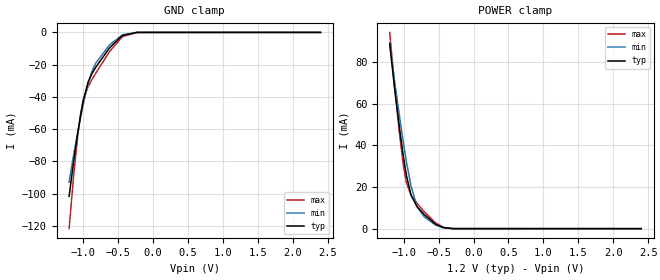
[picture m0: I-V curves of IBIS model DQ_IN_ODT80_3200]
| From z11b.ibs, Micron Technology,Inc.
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| MODEL DQ_IN_ODT80_3200 (Data Input with 80ohm ODT, 1600-3200Mbps)
[Model]   DQ_IN_ODT80_3200
Model_type   Input
Vinl = 905.000mV
Vinh = 1015.000mV
|   typ   min   max
|C_comp   0.764pF   0.710pF   0.826pF
C_comp_power_clamp   0.382pF   0.355pF   0.413pF
C_comp_gnd_clamp   0.382pF   0.355pF   0.413pF
| Note: C_comp changes when the ODT circuit is enabled.
|[Model Spec]
| Dynamic Overshoot Parameters from DDR4 Specification
|D_overshoot_ampl_h   0.40   NA   NA
|D_overshoot_ampl_l   0.40   NA   NA
|D_overshoot_area_h   0.0800n   NA   NA
|D_overshoot_area_l   0.0800n   NA   NA
[Voltage Range]   1.2000V   1.1400V   1.2600V
| Junction Temperature (Ambient temp is 35C typ, 95C min, 0C max)
[Temperature Range]   50.0   110.0   0.0
[Add Submodel]
| Submodel Name   Mode
80ohm_ODT_3200   Non-Driving
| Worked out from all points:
|   GND clamp passes 1 mA (typ) near -0.39 V on its own axis
|   POWER clamp passes 1 mA (typ) near -0.48 V on its own axis
[GND_clamp]
|   Voltage   I(typ)   I(min)   I(max)
-1.2V     -101.7mA   -92.86mA   -121.7mA
-1.135V   -79.96mA   -75.85mA   -88.92mA
-1.08V    -63.49mA   -62.76mA   -65.41mA
-1.036V   -51.56mA   -52.84mA   -50.64mA
-992.7mV  -41.38mA   -43.58mA   -41.02mA
-927.3mV  -30.76mA   -31.6mA    -33.57mA
-872.7mV  -25.55mA   -24.13mA   -29.29mA
-818.2mV  -21.61mA   -19.01mA   -25.29mA
-621.8mV  -9.659mA   -7.799mA   -11.96mA
-436.4mV  -1.919mA   -1.478mA   -2.611mA
-229.1mV  -17.22uA   -19.75uA   -20.83uA
2.4V      0A         0A         0A
[Power Clamp]
|   Voltage   I(typ)   I(min)   I(max)
-1.2V     88.83mA    89.6mA     94.34mA
-1.135V   68.72mA    72.21mA    70.04mA
-1.058V   47.72mA    53.58mA    44.98mA
-1.004V   34.46mA    41.14mA    30.25mA
-960mV    25.46mA    31.98mA    21.99mA
-894.5mV  16.03mA    20.41mA    16.05mA
-807.3mV  10.5mA     10.53mA    12.15mA
-709.1mV  6.909mA    5.768mA    8.277mA
-545.5mV  2.223mA    1.735mA    2.842mA
-436.4mV  532.9uA    427.3uA    716.1uA
-294.5mV  16.21uA    18.63uA    20.69uA
2.4V      0A         0A         0A
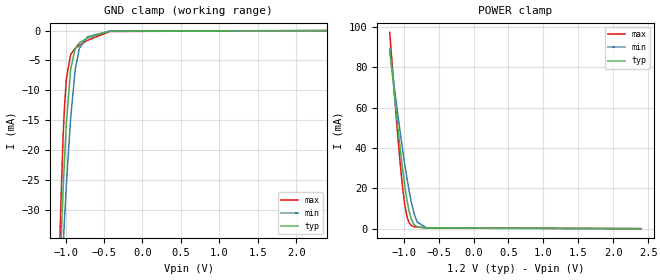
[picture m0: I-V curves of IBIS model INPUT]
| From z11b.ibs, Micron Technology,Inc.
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| MODEL INPUT (Add/Cmd/Ctrl Input Model, 1600-3200Mbps)
[Model]   INPUT
Model_type   Input
Vinl = 510.000mV
Vinh = 690.000mV
|   typ   min   max
|C_comp   0.306pF   0.256pF   0.356pF
C_comp_power_clamp   0.153pF   0.128pF   0.178pF
C_comp_gnd_clamp   0.153pF   0.128pF   0.178pF
[Model Spec]
| Input threshold voltage corners
Vinl   0.5100V   0.4800V   0.5400V
Vinh   0.6900V   0.6600V   0.7200V
| Dynamic Overshoot Parameters from DDR4 Specification
|D_overshoot_ampl_h   0.30   NA   NA
|D_overshoot_ampl_l   0.30   NA   NA
|D_overshoot_area_h   0.1754n   NA   NA
|D_overshoot_area_l   0.1762n   NA   NA
[Receiver Thresholds]
Vth   =  0.600V
Vth_min  =  0.5880V
Vth_max  =  0.6120V
Vinh_ac  =  0.090V
Vinh_dc  =  0.065V
Vinl_ac  = -0.090V
Vinl_dc  = -0.065V
Tslew_ac =  5.000ns |Not specified, so set to high value
Threshold_sensitivity = 0.50
Reference_supply Power_clamp_ref
[Voltage Range]   1.2000V   1.1400V   1.2600V
[POWER Clamp Reference]   1.2000V   1.1400V   1.2600V
| Junction Temperature (Ambient temp is 35C typ, 95C min, 0C max)
[Temperature Range]   50.0   110.0   0.0
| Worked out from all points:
|   GND clamp passes 1 mA (typ) near -0.67 V on its own axis
|   POWER clamp passes 1 mA (typ) near -0.81 V on its own axis
[GND Clamp]
|   Voltage   I(typ)   I(min)   I(max)
-1.2V     -89.68mA   -83.76mA   -112.5mA
-1.08V    -42.27mA   -48.6mA    -37.43mA
-1.065V   -37.02mA   -44.48mA   -30.24mA
-1.035V   -27.36mA   -36.67mA   -18.41mA
-1.015V   -21.61mA   -31.62mA   -12.71mA
-990mV    -15.4mA    -25.73mA   -8.028mA
-935mV    -6.48mA    -14.64mA   -4.005mA
-875mV    -2.985mA   -6.456mA   -2.943mA
-820mV    -2.025mA   -2.921mA   -2.441mA
-715mV    -1.243mA   -1.044mA   -1.636mA
-425mV    -95.71uA   -64.44uA   -150uA
2.4V      0A         0A         0A
[POWER Clamp]
|   Voltage   I(typ)   I(min)   I(max)
-1.2V     89.29mA    88mA       97.25mA
-1.095V   53.78mA    59.42mA    50.04mA
-1.05V    39.66mA    47.81mA    32.16mA
-1.015V   29.47mA    39.09mA    20.17mA
-985mV    21.54mA    31.96mA    11.96mA
-955mV    14.57mA    25.34mA    6.252mA
-925mV    9.043mA    19.2mA     3.084mA
-890mV    4.569mA    12.96mA    1.546mA
-850mV    1.945mA    7.193mA    981.4uA
-805mV    853.4uA    3.217mA    763.2uA
-665mV    277.9uA    269.6uA    403.6uA
2.4V      0A         0A         0A
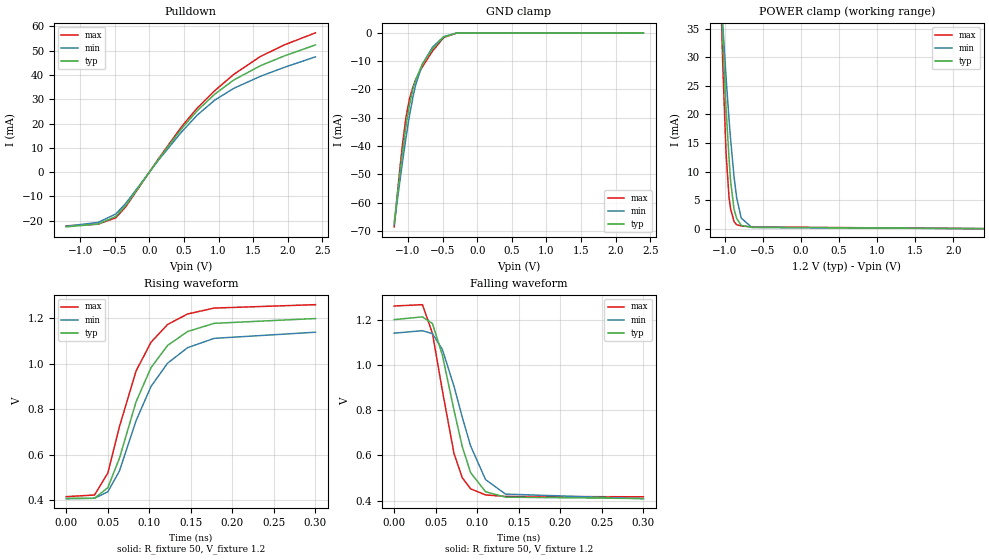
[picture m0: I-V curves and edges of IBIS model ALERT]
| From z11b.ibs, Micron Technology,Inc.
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| MODEL ALERT (ALERT_n Output Model, 1600-3200Mbps)
[Model]   ALERT
Model_type   Open_sink
Vmeas = 960.000mV
Vref = 1200.000mV
Cref = 0.0pF
Rref = 50.000Ohm
|   typ   min   max
|C_comp   0.806pF   0.756pF   0.856pF
C_comp_pulldown   0.806pF   0.756pF   0.856pF
[Model Spec]
| Timing spec test load voltage corners
Vref   1.2000V   1.1400V   1.2600V
[Voltage Range]   1.2000V   1.1400V   1.2600V
| Junction Temperature (Ambient temp is 35C typ, 95C min, 0C max)
[Temperature Range]   50.0   110.0   0.0
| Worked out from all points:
|   slope of the pulldown table from 0 to 0.18 V, typ, clamps not added: 25.2 ohm
|   GND clamp passes 1 mA (typ) near -0.46 V on its own axis
|   POWER clamp passes 1 mA (typ) near -0.82 V on its own axis
|   falling waveform, R_fixture 50, V_fixture 1.2: 20-80 % time 29.5ps typ, 35.7ps min, 25ps max; typ from 1.2 V to 0.409 V
|   rising waveform, R_fixture 50, V_fixture 1.2: 20-80 % time 50ps typ, 53ps min, 46.3ps max; typ from 0.409 V to 1.2 V
[Pulldown]
|   Voltage   I(typ)   I(min)   I(max)
-1.2V     -22.53mA   -22.3mA    -22.12mA
-740mV    -21.37mA   -20.69mA   -21.42mA
-485mV    -18.25mA   -17.25mA   -18.81mA
-340mV    -13.7mA    -12.84mA   -14.26mA
130mV     5.188mA    4.823mA    5.434mA
465mV     17.81mA    16.51mA    18.66mA
690mV     25.22mA    23.41mA    26.3mA
945mV     32.09mA    29.63mA    33.52mA
1.22V     37.91mA    34.47mA    40.23mA
1.605V    43.79mA    39.44mA    47.59mA
1.955V    47.87mA    43.16mA    52.41mA
2.4V      52.35mA    47.43mA    57.32mA
[GND Clamp]
|   Voltage   I(typ)   I(min)   I(max)
-1.2V     -67.18mA   -67.87mA   -68.61mA
-1.125V   -51.16mA   -53.75mA   -49.62mA
-1.08V    -42.22mA   -45.67mA   -39.36mA
-1.03V    -33.13mA   -37.16mA   -29.91mA
-980mV    -25.55mA   -29.4mA    -23.39mA
-925mV    -19.39mA   -22.21mA   -18.78mA
-890mV    -16.63mA   -18.38mA   -16.54mA
-790mV    -10.9mA    -10.95mA   -11.9mA
-645mV    -5.66mA    -5.033mA   -6.4mA
-485mV    -1.483mA   -1.321mA   -1.687mA
-290mV    -27.81uA   -35.65uA   -21.31uA
2.4V      0A         0A         0A
[POWER Clamp]
|   Voltage   I(typ)   I(min)   I(max)
-1.2V     93.15mA    76.36mA    125mA
-1.06V    43.2mA     42.87mA    44.2mA
-1.04V    36.92mA    38.31mA    34.41mA
-1.03V    33.78mA    36.15mA    29.65mA
-985mV    21.11mA    26.63mA    13.27mA
-945mV    12.23mA    19.01mA    5.357mA
-925mV    8.349mA    15.67mA    3.504mA
-880mV    3.388mA    9.098mA    1.221mA
-845mV    1.787mA    5.39mA     688uA
-785mV    565.7uA    1.842mA    471.7uA
-645mV    233.3uA    213.3uA    304.2uA
2.4V      0A         0A         0A
[Ramp]
|   typ   min   max
| 20% - 80%
dV/dt_r   474.09m/49.94p   438.51m/52.92p   505.63m/46.25p
dV/dt_f   474.26m/29.47p   438.65m/35.66p   505.66m/25.03p
| 25% - 75%
|dV/dt_r   395.07m/39.27p   365.43m/41.65p   421.36m/36.41p
|dV/dt_f   395.22m/23.78p   365.54m/28.72p   421.39m/20.13p
R_load = 50
[Falling Waveform]
R_fixture   = 50
V_fixture   = 1.2
V_fixture_min = 1.14
V_fixture_max = 1.26
|   Time   V(typ)   V(min)   V(max)
0s        1.2V       1.14V      1.26V
34ps      1.212V     1.151V     1.266V
46ps      1.183V     1.138V     1.14V
58ps      1.043V     1.068V     886.6mV
72ps      799.6mV    905.2mV    608.3mV
82ps      637.8mV    768mV      500.4mV
92ps      523.6mV    641.8mV    452.2mV
110ps     439.2mV    492.8mV    425.1mV
134ps     415.2mV    428.8mV    418.4mV
300ps     409.1mV    408.5mV    416.8mV
[Rising Waveform]
R_fixture   = 50
V_fixture   = 1.2
V_fixture_min = 1.14
V_fixture_max = 1.26
|   Time   V(typ)   V(min)   V(max)
0s        409mV      407.9mV    416.8mV
34ps      409.9mV    409.7mV    424mV
50ps      456.2mV    438.2mV    520.4mV
64ps      585.6mV    529.3mV    724.3mV
84ps      833.3mV    750.3mV    968.5mV
102ps     983.4mV    900.8mV    1.095V
122ps     1.081V     1.003V     1.173V
146ps     1.142V     1.071V     1.219V
178ps     1.178V     1.112V     1.245V
300ps     1.199V     1.139V     1.26V
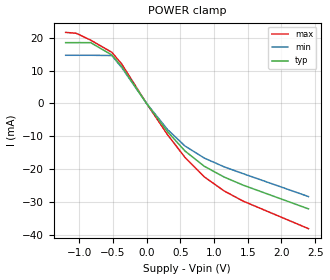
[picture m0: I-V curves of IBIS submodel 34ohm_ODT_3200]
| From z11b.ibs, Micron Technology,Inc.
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| SUBMODEL 34ohm_ODT_3200
[Submodel]   34ohm_ODT_3200
Submodel_type  Dynamic_clamp
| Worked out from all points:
|   POWER clamp passes 1 mA (typ) near -0.03 V on its own axis
[POWER Clamp]
|   Voltage   I(typ)   I(min)   I(max)
-1.2V     18.53mA    14.68mA    21.64mA
-1.045V   18.53mA    14.68mA    21.38mA
-830mV    18.53mA    14.68mA    19.29mA
-515mV    14.76mA    14.59mA    15.57mA
-370mV    11.26mA    10.96mA    12.05mA
0V        81.74nA    77.62nA    81.84nA
310mV     -8.572mA   -7.927mA   -9.489mA
570mV     -14.49mA   -12.96mA   -16.44mA
855mV     -19.11mA   -16.62mA   -22.34mA
1.15V     -22.4mA    -19.29mA   -26.63mA
1.43V     -24.85mA   -21.36mA   -29.71mA
2.4V      -32.09mA   -28.34mA   -38.11mA
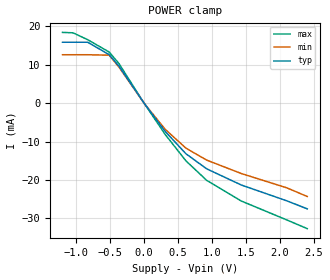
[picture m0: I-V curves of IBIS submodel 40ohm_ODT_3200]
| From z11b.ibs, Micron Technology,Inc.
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| SUBMODEL 40ohm_ODT_3200
[Submodel]   40ohm_ODT_3200
Submodel_type  Dynamic_clamp
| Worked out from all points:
|   POWER clamp passes 1 mA (typ) near -0.04 V on its own axis
[POWER Clamp]
|   Voltage   I(typ)   I(min)   I(max)
-1.2V     15.88mA    12.62mA    18.44mA
-1.045V   15.88mA    12.62mA    18.33mA
-830mV    15.88mA    12.62mA    16.54mA
-515mV    12.65mA    12.51mA    13.34mA
-370mV    9.654mA    9.398mA    10.33mA
0V        66.76nA    68.51nA    78.99nA
310mV     -7.348mA   -6.795mA   -8.134mA
615mV     -13.16mA   -11.7mA    -15mA
920mV     -17.08mA   -14.81mA   -20.08mA
1.43V     -21.3mA    -18.31mA   -25.47mA
2.1V      -25.42mA   -22.04mA   -30.4mA
2.4V      -27.51mA   -24.29mA   -32.66mA
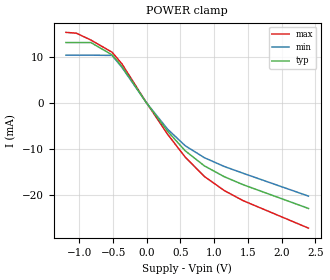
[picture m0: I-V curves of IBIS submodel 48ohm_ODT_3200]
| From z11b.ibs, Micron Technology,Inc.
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| SUBMODEL 48ohm_ODT_3200
[Submodel]   48ohm_ODT_3200
Submodel_type  Dynamic_clamp
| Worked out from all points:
|   POWER clamp passes 1 mA (typ) near -0.05 V on its own axis
[POWER Clamp]
|   Voltage   I(typ)   I(min)   I(max)
-1.2V     13.23mA    10.48mA    15.45mA
-1.045V   13.23mA    10.48mA    15.27mA
-830mV    13.23mA    10.48mA    13.78mA
-515mV    10.54mA    10.43mA    11.12mA
-370mV    8.047mA    7.834mA    8.608mA
0V        61.64nA    54.48nA    66.07nA
310mV     -6.125mA   -5.664mA   -6.78mA
570mV     -10.36mA   -9.257mA   -11.74mA
855mV     -13.65mA   -11.87mA   -15.96mA
1.15V     -16.01mA   -13.78mA   -19.03mA
1.43V     -17.75mA   -15.26mA   -21.23mA
2.4V      -22.93mA   -20.24mA   -27.22mA
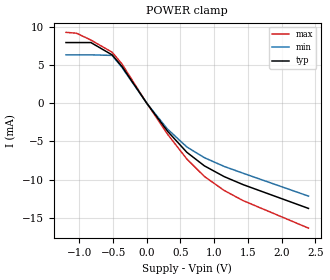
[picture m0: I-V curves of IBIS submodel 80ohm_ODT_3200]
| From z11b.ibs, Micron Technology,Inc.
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| SUBMODEL 80ohm_ODT_3200
[Submodel]   80ohm_ODT_3200
Submodel_type  Dynamic_clamp
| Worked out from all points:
|   POWER clamp passes 1 mA (typ) near -0.08 V on its own axis
[POWER Clamp]
|   Voltage   I(typ)   I(min)   I(max)
-1.2V     7.942mA    6.335mA    9.274mA
-1.045V   7.942mA    6.335mA    9.168mA
-830mV    7.942mA    6.335mA    8.273mA
-515mV    6.329mA    6.259mA    6.677mA
-370mV    4.831mA    4.703mA    5.168mA
0V        40.32nA    37.49nA    44.84nA
310mV     -3.677mA   -3.4mA     -4.07mA
595mV     -6.423mA   -5.723mA   -7.305mA
855mV     -8.192mA   -7.123mA   -9.58mA
1.15V     -9.605mA   -8.271mA   -11.42mA
1.43V     -10.65mA   -9.158mA   -12.74mA
2.4V      -13.76mA   -12.15mA   -16.34mA
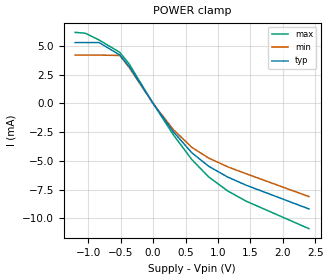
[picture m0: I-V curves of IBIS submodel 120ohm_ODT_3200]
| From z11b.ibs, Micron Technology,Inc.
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| SUBMODEL 120ohm_ODT_3200
[Submodel]   120ohm_ODT_3200
Submodel_type  Dynamic_clamp
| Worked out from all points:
|   POWER clamp passes 1 mA (typ) near -0.12 V on its own axis
[POWER Clamp]
|   Voltage   I(typ)   I(min)   I(max)
-1.2V     5.293mA    4.206mA    6.18mA
-1.045V   5.293mA    4.206mA    6.111mA
-830mV    5.293mA    4.206mA    5.515mA
-515mV    4.219mA    4.173mA    4.451mA
-370mV    3.221mA    3.136mA    3.446mA
0V        30.43nA    22.74nA    36.21nA
310mV     -2.451mA   -2.267mA   -2.714mA
595mV     -4.282mA   -3.815mA   -4.87mA
855mV     -5.462mA   -4.749mA   -6.387mA
1.15V     -6.404mA   -5.514mA   -7.613mA
1.43V     -7.103mA   -6.106mA   -8.492mA
2.4V      -9.174mA   -8.101mA   -10.89mA
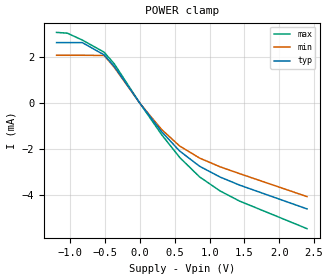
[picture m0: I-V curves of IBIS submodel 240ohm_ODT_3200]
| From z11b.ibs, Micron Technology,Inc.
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| SUBMODEL 240ohm_ODT_3200
[Submodel]   240ohm_ODT_3200
Submodel_type  Dynamic_clamp
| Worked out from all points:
|   POWER clamp passes 1 mA (typ) near -0.23 V on its own axis
[POWER Clamp]
|   Voltage   I(typ)   I(min)   I(max)
-1.2V     2.648mA    2.096mA    3.091mA
-1.045V   2.648mA    2.096mA    3.057mA
-830mV    2.648mA    2.096mA    2.759mA
-515mV    2.11mA     2.087mA    2.226mA
-370mV    1.611mA    1.569mA    1.723mA
0V        19.82nA    13.7nA     25.59nA
310mV     -1.226mA   -1.134mA   -1.357mA
570mV     -2.072mA   -1.853mA   -2.35mA
855mV     -2.731mA   -2.375mA   -3.194mA
1.15V     -3.202mA   -2.757mA   -3.807mA
1.43V     -3.552mA   -3.053mA   -4.247mA
2.4V      -4.589mA   -4.053mA   -5.448mA
